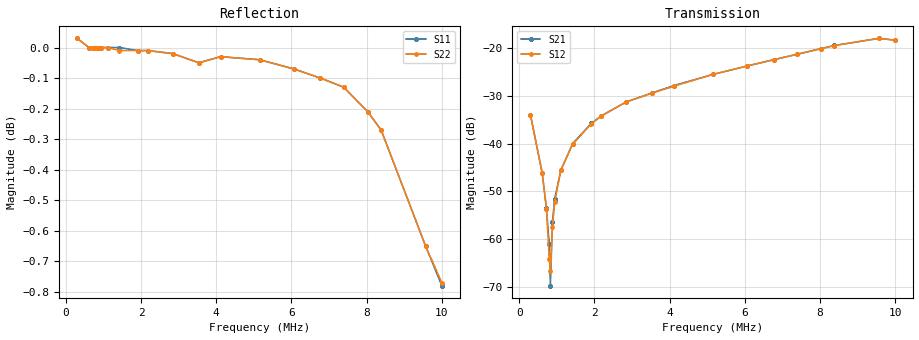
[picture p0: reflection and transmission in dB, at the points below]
!s-Parameter Generated by FASTRON Sdn. Bhd.
!FASTRON P/N : 1812AFTC-242X
!Keysight Technologies: E5071C_MY46733604_B.14.02
!Date: Wed Mar 18 14:00:06 2026
!Version  :Rev00  Wed Mar 18 14:00:06 2026
!Data & Calibration Information:
!Freq  S11:SOLT2(ON)  S21:SOLT2(ON)  S12:SOLT2(ON)  S22:SOLT2(ON)
!PortZ  Port1:50+j0  Port2:50+j0
!When reading reference impedance value at option line is always used.
! Remarks : This data is being provided solely for informational purposes.
# Hz S dB R 50
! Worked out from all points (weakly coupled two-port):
!   1601 points, 300 kHz to 10 MHz, reference 50 ohm
!   highest |S21| = -17.97 dB at 9.568 MHz (marker M1); lowest = -69.8 dB at 830.1 kHz (marker M2)
!   lowest |S11| = -0.8 dB at 10 MHz (marker M3), VSWR 22.43, Z = 33 - j183 ohm
!   |S11| at or under -10 dB: nowhere
!   |S22| runs from -0.8 to 0.0 dB; largest |S21 - S12| = 0.00091
!   S11 on the Smith chart (normalised r, x): 300 kHz: -0, +11; 2.185 MHz: 0.00, +1.37; 4.114 MHz: 0.00, +0.41; 6.061 MHz: 0.00, -0.17; 8.029 MHz: 0.02, -0.90; 10 MHz: 0.66, -3.66
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300000  0.03 10.9  -33.95 -87.7  -33.98 -87.1  0.03 -10.2
611603  0.00 20.6  -46.07 -84.7  -46.22 -83.7  -0.00 -22.3
725834  -0.00 24.3  -53.51 -78.4  -53.71 -78.6  -0.00 -26.7
799861  -0.00 26.7  -61.08 -24.6  -64.16 -28.9  -0.00 -29.5
830077  0.00 27.7  -69.76 57.0  -66.61 32.6  -0.00 -30.6
884466  -0.00 29.5  -56.34 67.7  -57.51 65.4  -0.00 -32.7
942884  -0.00 31.4  -51.56 76.1  -52.28 80.0  -0.00 -34.8
1107412  -0.00 36.7  -45.61 83.2  -45.56 81.7  -0.00 -41.0
1420553  -0.00 47.0  -39.99 82.6  -40.17 83.4  -0.01 -52.7
1917564  -0.01 63.4  -35.77 82.8  -35.86 81.9  -0.01 -71.3
2184619  -0.01 72.1  -34.17 81.9  -34.25 82.1  -0.01 -81.3
2849500  -0.02 94.0  -31.26 80.5  -31.27 80.7  -0.02 -106.1
3534704  -0.05 116.6  -29.39 73.8  -29.45 74.1  -0.05 -131.6
4113955  -0.03 135.7  -27.84 77.1  -27.98 77.1  -0.03 -153.2
5155786  -0.04 169.9  -25.51 74.6  -25.51 74.7  -0.04 167.9
6060658  -0.07 -160.4  -23.77 71.8  -23.73 71.6  -0.07 134.0
6770355  -0.10 -137.2  -22.44 68.9  -22.43 69.0  -0.10 107.5
7390266  -0.13 -117.0  -21.30 65.7  -21.29 65.5  -0.13 84.1
8028618  -0.21 -96.2  -20.11 61.0  -20.12 61.0  -0.21 60.0
8385344  -0.27 -84.7  -19.44 57.5  -19.47 57.4  -0.27 46.6
9568174  -0.65 -45.2  -17.97 37.1  -17.96 37.1  -0.65 3.0
1e7  -0.78 -29.7  -18.34 27.0  -18.33 27.0  -0.77 -11.9
